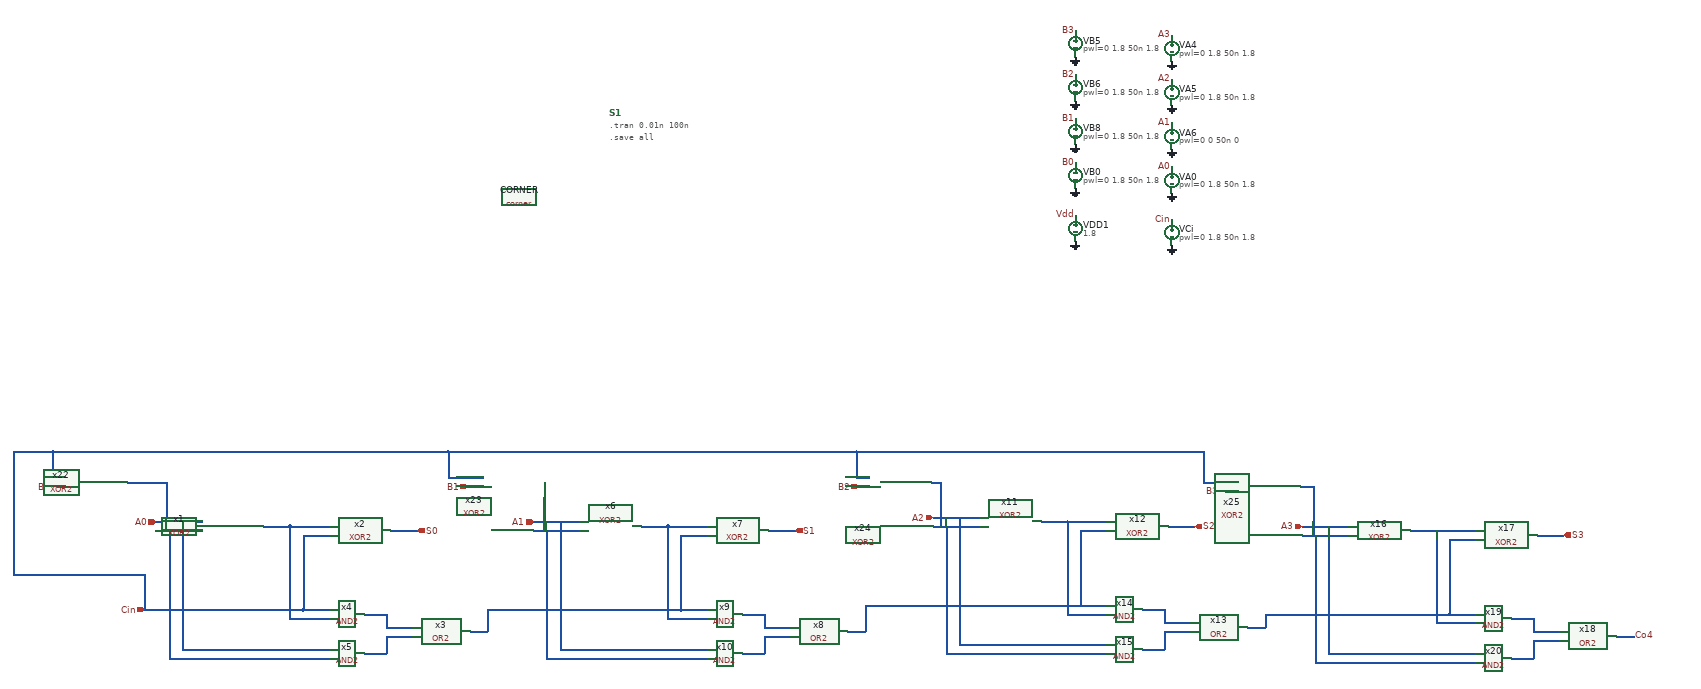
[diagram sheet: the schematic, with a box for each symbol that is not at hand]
v {xschem version=3.4.5 file_version=1.2
}
G {}
K {}
V {}
S {}
E {}
B 2 2558 -2763 3358 -2363 {flags=graph
y1=0
y2=2
ypos1=-0.27313425
ypos2=1.7268657

subdivy=1
unity=1
x1=1.9173866e-09
x2=1.0191737e-07


xlabmag=1.0
ylabmag=1.0


dataset=-1
unitx=1
logx=0
logy=0
divx=10
divy=5
subdivx=1
digital=1


color="11 11 11 4 4"
node="a;a3,a2,a1,a0
b;b3,b2,b1,b0
s;s3,s2,s1,s0
sum;co4,s3,s2,s1,s0
co4"}
N 1850 -1470 1850 -1440 {
lab=#net1}
N 1850 -1440 1910 -1440 {
lab=#net1}
N 1850 -1420 1850 -1380 {
lab=#net2}
N 1850 -1420 1910 -1420 {
lab=#net2}
N 1660 -1650 1720 -1650 {
lab=Cin}
N 1660 -1650 1660 -1490 {
lab=Cin}
N 1660 -1490 1660 -1480 {
lab=Cin}
N 1660 -1480 1720 -1480 {
lab=Cin}
N 1630 -1460 1720 -1460 {
lab=#net3}
N 1630 -1670 1630 -1460 {
lab=#net3}
N 1630 -1670 1720 -1670 {
lab=#net3}
N 1570 -1670 1630 -1670 {
lab=#net3}
N 1800 -1470 1850 -1470 {
lab=#net1}
N 1800 -1380 1850 -1380 {
lab=#net2}
N 2040 -1430 2080 -1430 {
lab=#net4}
N 1860 -1660 1920 -1660 {
lab=S0}
N 1325 -1680 1430 -1680 {
lab=A0}
N 1325 -1660 1430 -1660 {
lab=#net5}
N 1385 -1390 1720 -1390 {
lab=A0}
N 1385 -1680 1385 -1390 {
lab=A0}
N 1355 -1370 1720 -1370 {
lab=#net5}
N 1355 -1660 1355 -1370 {
lab=#net5}
N 1330 -1480 1660 -1480 {
lab=Cin}
N 2710 -1470 2710 -1440 {
lab=#net6}
N 2710 -1440 2770 -1440 {
lab=#net6}
N 2710 -1420 2710 -1380 {
lab=#net7}
N 2710 -1420 2770 -1420 {
lab=#net7}
N 2520 -1650 2580 -1650 {
lab=#net4}
N 2520 -1650 2520 -1490 {
lab=#net4}
N 2520 -1490 2520 -1480 {
lab=#net4}
N 2520 -1480 2580 -1480 {
lab=#net4}
N 2490 -1460 2580 -1460 {
lab=#net8}
N 2490 -1670 2490 -1460 {
lab=#net8}
N 2490 -1670 2580 -1670 {
lab=#net8}
N 2430 -1670 2490 -1670 {
lab=#net8}
N 2660 -1470 2710 -1470 {
lab=#net6}
N 2660 -1380 2710 -1380 {
lab=#net7}
N 2900 -1430 2940 -1430 {
lab=#net9}
N 2720 -1660 2780 -1660 {
lab=S1}
N 2185 -1680 2290 -1680 {
lab=A1}
N 2185 -1660 2290 -1660 {
lab=#net10}
N 2245 -1390 2580 -1390 {
lab=A1}
N 2245 -1680 2245 -1390 {
lab=A1}
N 2215 -1370 2580 -1370 {
lab=#net10}
N 2215 -1660 2215 -1370 {
lab=#net10}
N 2190 -1480 2520 -1480 {
lab=#net4}
N 3620 -1480 3620 -1450 {
lab=#net11}
N 3620 -1450 3680 -1450 {
lab=#net11}
N 3620 -1430 3620 -1390 {
lab=#net12}
N 3620 -1430 3680 -1430 {
lab=#net12}
N 3430 -1660 3490 -1660 {
lab=#net9}
N 3430 -1660 3430 -1500 {
lab=#net9}
N 3430 -1500 3430 -1490 {
lab=#net9}
N 3430 -1490 3490 -1490 {
lab=#net9}
N 3400 -1470 3490 -1470 {
lab=#net13}
N 3400 -1680 3400 -1470 {
lab=#net13}
N 3400 -1680 3490 -1680 {
lab=#net13}
N 3340 -1680 3400 -1680 {
lab=#net13}
N 3570 -1480 3620 -1480 {
lab=#net11}
N 3570 -1390 3620 -1390 {
lab=#net12}
N 3810 -1440 3850 -1440 {
lab=#net14}
N 3630 -1670 3690 -1670 {
lab=S2}
N 3095 -1690 3200 -1690 {
lab=A2}
N 3095 -1670 3200 -1670 {
lab=#net15}
N 3155 -1400 3490 -1400 {
lab=A2}
N 3155 -1690 3155 -1400 {
lab=A2}
N 3125 -1380 3490 -1380 {
lab=#net15}
N 3125 -1670 3125 -1380 {
lab=#net15}
N 3100 -1490 3430 -1490 {
lab=#net9}
N 4270 -1640 4330 -1640 {
lab=#net14}
N 4270 -1640 4270 -1480 {
lab=#net14}
N 4270 -1480 4270 -1470 {
lab=#net14}
N 4270 -1470 4330 -1470 {
lab=#net14}
N 4240 -1450 4330 -1450 {
lab=#net16}
N 4650 -1420 4690 -1420 {
lab=Co4}
N 4470 -1650 4530 -1650 {
lab=S3}
N 3935 -1670 4040 -1670 {
lab=A3}
N 3935 -1650 4040 -1650 {
lab=#net17}
N 3995 -1380 4330 -1380 {
lab=A3}
N 3995 -1670 3995 -1380 {
lab=A3}
N 3965 -1360 4330 -1360 {
lab=#net17}
N 3965 -1650 3965 -1360 {
lab=#net17}
N 3940 -1470 4270 -1470 {
lab=#net14}
N 1300 -1480 1330 -1480 {
lab=Cin}
N 4460 -1430 4520 -1430 {
lab=#net18}
N 4460 -1460 4460 -1430 {
lab=#net18}
N 4410 -1460 4460 -1460 {
lab=#net18}
N 4180 -1660 4330 -1660 {
lab=#net16}
N 4240 -1660 4240 -1450 {
lab=#net16}
N 4460 -1410 4520 -1410 {
lab=#net19}
N 4460 -1410 4460 -1370 {
lab=#net19}
N 4410 -1370 4460 -1370 {
lab=#net19}
N 1100 -1760 1120 -1760 {
lab=B0}
N 1260 -1770 1350 -1770 {
lab=#net5}
N 1350 -1770 1350 -1660 {
lab=#net5}
N 2030 -1760 2070 -1760 {
lab=B1}
N 2210 -1770 2210 -1660 {
lab=#net10}
N 3090 -1770 3110 -1770 {
lab=#net15}
N 3110 -1770 3110 -1670 {
lab=#net15}
N 2920 -1760 2950 -1760 {
lab=B2}
N 3930 -1760 3960 -1760 {
lab=#net17}
N 3960 -1760 3960 -1650 {
lab=#net17}
N 3760 -1750 3790 -1750 {
lab=B3}
N 3710 -1770 3790 -1770 {
lab=Cin}
N 3710 -1840 3710 -1770 {
lab=Cin}
N 2920 -1840 3710 -1840 {
lab=Cin}
N 2920 -1840 2920 -1780 {
lab=Cin}
N 2920 -1780 2950 -1780 {
lab=Cin}
N 1990 -1840 2920 -1840 {
lab=Cin}
N 1990 -1840 1990 -1790 {
lab=Cin}
N 1990 -1790 1990 -1780 {
lab=Cin}
N 1990 -1780 2070 -1780 {
lab=Cin}
N 1090 -1840 1990 -1840 {
lab=Cin}
N 1090 -1840 1090 -1780 {
lab=Cin}
N 1090 -1780 1120 -1780 {
lab=Cin}
N 1000 -1840 1090 -1840 {
lab=Cin}
N 1000 -1840 1000 -1560 {
lab=Cin}
N 1000 -1560 1300 -1560 {
lab=Cin}
N 1300 -1560 1300 -1480 {
lab=Cin}
N 2080 -1480 2080 -1430 {
lab=#net4}
N 2080 -1480 2190 -1480 {
lab=#net4}
N 3850 -1470 3850 -1440 {
lab=#net14}
N 3850 -1470 3940 -1470 {
lab=#net14}
N 2940 -1490 2940 -1430 {
lab=#net9}
N 2940 -1490 3100 -1490 {
lab=#net9}
C {XOR2.sym} 1490 -1670 0 0 {name=x1}
C {XOR2.sym} 1780 -1660 0 0 {name=x2}
C {OR2.sym} 1960 -1430 0 0 {name=x3}
C {AND2.sym} 1760 -1470 0 0 {name=x4}
C {AND2.sym} 1760 -1380 0 0 {name=x5}
C {devices/opin.sym} 1920 -1660 0 0 {name=p4 lab=S0}
C {devices/ipin.sym} 1325 -1680 0 0 {name=p1 sig_type=std_logic lab=A0}
C {devices/ipin.sym} 1105 -1760 0 0 {name=p2 sig_type=std_logic lab=B0}
C {devices/ipin.sym} 1300 -1480 0 0 {name=p3 sig_type=std_logic lab=Cin}
C {XOR2.sym} 2350 -1670 0 0 {name=x6}
C {XOR2.sym} 2640 -1660 0 0 {name=x7}
C {OR2.sym} 2820 -1430 0 0 {name=x8}
C {AND2.sym} 2620 -1470 0 0 {name=x9}
C {AND2.sym} 2620 -1380 0 0 {name=x10}
C {devices/opin.sym} 2780 -1660 0 0 {name=p8 lab=S1}
C {devices/ipin.sym} 2185 -1680 0 0 {name=p10 sig_type=std_logic lab=A1}
C {devices/ipin.sym} 2035 -1760 0 0 {name=p11 sig_type=std_logic lab=B1}
C {XOR2.sym} 3260 -1680 0 0 {name=x11}
C {XOR2.sym} 3550 -1670 0 0 {name=x12}
C {OR2.sym} 3730 -1440 0 0 {name=x13}
C {AND2.sym} 3530 -1480 0 0 {name=x14}
C {AND2.sym} 3530 -1390 0 0 {name=x15}
C {devices/opin.sym} 3690 -1670 0 0 {name=p17 lab=S2}
C {devices/ipin.sym} 3095 -1690 0 0 {name=p19 sig_type=std_logic lab=A2}
C {devices/ipin.sym} 2925 -1760 0 0 {name=p20 sig_type=std_logic lab=B2}
C {XOR2.sym} 4100 -1660 0 0 {name=x16}
C {XOR2.sym} 4390 -1650 0 0 {name=x17}
C {OR2.sym} 4570 -1420 0 0 {name=x18}
C {AND2.sym} 4370 -1460 0 0 {name=x19}
C {AND2.sym} 4370 -1370 0 0 {name=x20}
C {devices/opin.sym} 4530 -1650 0 0 {name=p24 lab=S3}
C {devices/ipin.sym} 3935 -1670 0 0 {name=p26 sig_type=std_logic lab=A3}
C {devices/ipin.sym} 3765 -1750 0 0 {name=p27 sig_type=std_logic lab=B3}
C {devices/lab_pin.sym} 4690 -1420 2 0 {name=p13 lab=Co4}
C {XOR2.sym} 1180 -1770 0 0 {name=x22}
C {XOR2.sym} 2130 -1770 0 0 {name=x23}
C {XOR2.sym} 3010 -1770 0 0 {name=x24}
C {XOR2.sym} 3850 -1760 0 0 {name=x25}
C {devices/vsource.sym} 3638 -2758 0 0 {name=VA4 value="pwl=0 1.8 50n 1.8" savecurrent=false}
C {devices/lab_pin.sym} 3638 -2788 0 0 {name=p38 sig_type=std_logic lab=A3}
C {devices/vsource.sym} 3638 -2658 0 0 {name=VA5 value="pwl=0 1.8 50n 1.8 " savecurrent=false}
C {devices/lab_pin.sym} 3638 -2688 0 0 {name=p39 sig_type=std_logic lab=A2}
C {devices/vsource.sym} 3638 -2558 0 0 {name=VA6 value="pwl=0 0 50n 0 " savecurrent=false}
C {devices/lab_pin.sym} 3638 -2588 0 0 {name=p40 sig_type=std_logic lab=A1}
C {devices/vsource.sym} 3638 -2458 0 0 {name=VA0 value="pwl=0 1.8 50n 1.8" savecurrent=false}
C {devices/lab_pin.sym} 3638 -2488 0 0 {name=VA7 sig_type=std_logic lab=A0}
C {devices/vsource.sym} 3418 -2768 0 0 {name=VB5 value="pwl=0 1.8 50n 1.8 " savecurrent=false}
C {devices/lab_pin.sym} 3418 -2798 0 0 {name=VB4 sig_type=std_logic lab=B3}
C {devices/vsource.sym} 3418 -2668 0 0 {name=VB6 value="pwl=0 1.8 50n 1.8 " savecurrent=false}
C {devices/lab_pin.sym} 3418 -2698 0 0 {name=VB7 sig_type=std_logic lab=B2}
C {devices/vsource.sym} 3418 -2568 0 0 {name=VB8 value="pwl=0 1.8 50n 1.8 " savecurrent=false}
C {devices/lab_pin.sym} 3418 -2598 0 0 {name=VB9 sig_type=std_logic lab=B1}
C {devices/vsource.sym} 3418 -2468 0 0 {name=VB0 value="pwl=0 1.8 50n 1.8" savecurrent=false}
C {devices/lab_pin.sym} 3418 -2498 0 0 {name=VB10 sig_type=std_logic lab=B0}
C {devices/gnd.sym} 3638 -2428 0 0 {name=l7 lab=GND}
C {devices/gnd.sym} 3418 -2438 0 0 {name=l8 lab=GND}
C {devices/gnd.sym} 3638 -2528 0 0 {name=l15 lab=GND}
C {devices/gnd.sym} 3418 -2538 0 0 {name=l16 lab=GND}
C {devices/gnd.sym} 3638 -2628 0 0 {name=l17 lab=GND}
C {devices/gnd.sym} 3418 -2638 0 0 {name=l18 lab=GND}
C {devices/gnd.sym} 3418 -2738 0 0 {name=l19 lab=GND}
C {devices/gnd.sym} 3638 -2728 0 0 {name=l20 lab=GND}
C {devices/vsource.sym} 3638 -2338 0 0 {name=VCi value="pwl=0 1.8 50n 1.8 " savecurrent=false}
C {devices/lab_pin.sym} 3638 -2368 0 0 {name=Ci1 sig_type=std_logic lab=Cin}
C {devices/gnd.sym} 3638 -2308 0 0 {name=Ci2 lab=GND}
C {devices/vsource.sym} 3418 -2348 0 0 {name=VDD1 value=1.8 savecurrent=false}
C {devices/lab_pin.sym} 3418 -2378 0 0 {name=Ci3 sig_type=std_logic lab=Vdd}
C {devices/gnd.sym} 3418 -2318 0 0 {name=Ci4 lab=GND}
C {devices/code_shown.sym} 2357 -2610 0 0 {name=S1 only_toplevel=false value=".tran 0.01n 100n
.save all"}
C {sky130_fd_pr/corner.sym} 2152 -2420 0 0 {name=CORNER only_toplevel=true corner=tt}
